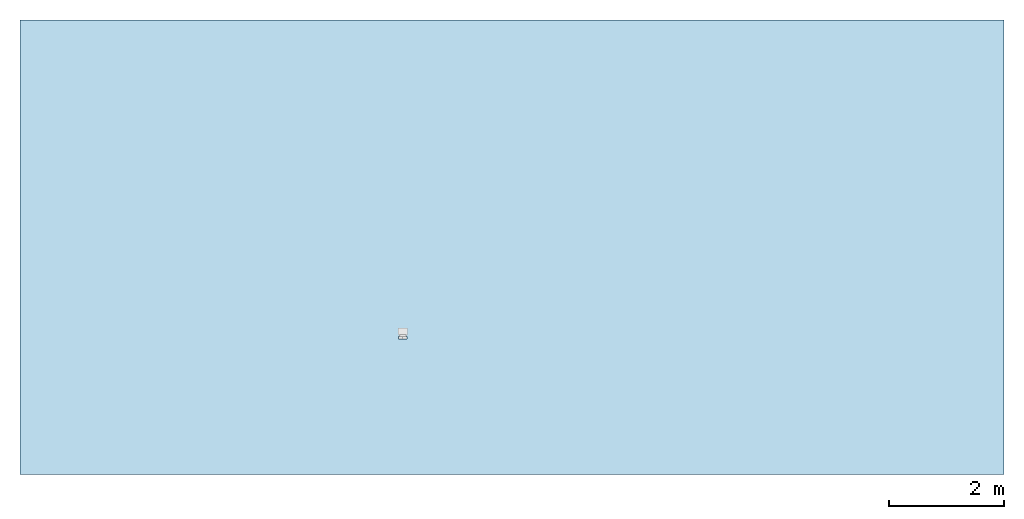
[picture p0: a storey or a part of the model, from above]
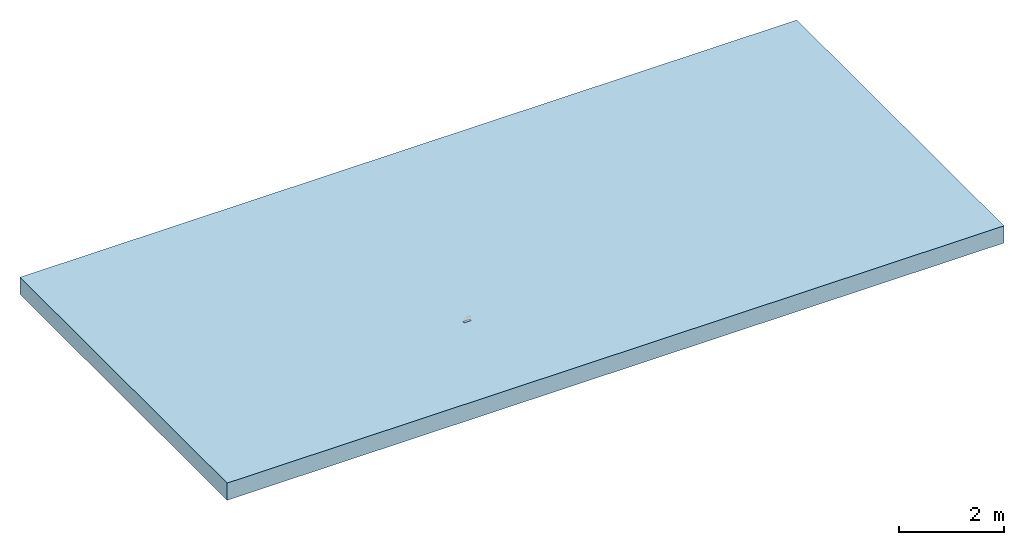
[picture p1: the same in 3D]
Properties of the parts of a building model (IFC2X3)

# File
Description: ViewDefinition [CoordinationView]
File name: 4962 - LH Inlet Outlet End cap.ifc
Time: 2013-08-30T17:54:13
Written by: Autodesk Revit 2013
Made in: 20120221_2030(x64)

# IfcProject, Project Number
LongName: Project Name; Phase: Project Status

# IfcSite, Default
RefLatitude: 42, 21, 30, 344238; RefLongitude: -71, -3, -35, -194702; RefElevation: 0 mm

# IfcBuilding
Pset_BuildingCommon - NumberOfStoreys: 1
Other - Project Address: ## Street City, State Zip; Project Number: Project Number; Project Name: Project Name; Project Status: Project Status; Project Issue Date: Issue Date; Client Name: Owner

# IfcBuildingStorey, Level 1
LongName: Level 1; Elevation: 0 mm
Constraints - Elevation Base: 0; Elevation: 0 mm
Graphics - Line Weight: 1; Line Pattern: Center; Symbol at End 2 Default: yes; Color: 0; Symbol at End 1 Default: no; Symbol: M_Level Head - Circle: M_Level Head - Circle
Dimensions - Computation Height: 0 mm
Identity Data - Building Story: yes; Structural: no; Name: Level 1

# IfcBuildingElementProxy: 4962 - LH Inlet/Outlet End cap, Civil-Drainage-Channel-ACO-KerbDrain-SP480:4962 - LH Inlet/Outlet End cap:4962 - LH Inlet/Outlet End cap:758980
In: Level 1
Material: Acetal Resin, Black, ACO Polymer Concrete
Construction - SP480-500: no; Inlet/Outlet-RH: no; EndCap: no; Inlet/Outlet-LH: yes
Constraints - Moves With Nearby Elements: no; Level: Level: Level 1
Phasing - Phase Created: New Construction
Dimensions - Volume: 2869491 mm3; Void_Ext_Start: -5.3 mm; Void_Ext_End: 155.2 mm; Endcap void width: 159.957 mm; Floor Opening Width: 150 mm; Void_Length: -50 mm; Endcap void depth: 359 mm
Pset_BuildingElementProxyCommon - Reference: 4962 - LH Inlet/Outlet End cap
General - TagNumber: 0.000000 0.000000; SerialNumber: 0.000000
Identity Data - Fax: +44 (0)1462 815895; Telephone: +44 (0)1462 816666; Product Page URL: http://www.aco.co.uk/product_detail.php?id=3; OmniClass Number: 23.70.50.24; Product Code: 4962; Installation guidelines: http://www.aco.co.uk/download.php?id=120; Maintenance guidelines: http://www.aco.co.uk/download.php?id=120; Address: ACO Business Park, Hitchin Road, Shefford, Bedfordshire, United Kingdom SG17 5TE; Product brochure: http://www.aco.co.uk/download.php?id=120; e-mail Sales: customersupport@aco.co.uk; Assembly Description: Rain Water Drainage; Price: POA - contact ACO; Cost: 0; Model: ACO KerbDrain SP480; e-mail Technical: technical@aco.co.uk; URL: www.aco.co.uk; Manufacturer: ACO Technologies plc - ACO Water Management Division; OmniClass Title: Rainwater Removal; Model Description: Combined kerb and drainage system; Assembly Code: D2040; Type Comments: ACO KerbDrain SP480 splayed LH outlet end cap
Data - Concrete Surround Volume - Load Class A 15 - D 400 - Concrete Pavement: N/A; Installation - Concrete Grade: N/A; Invert Depth: N/A; Hydraulic Performance: N/A; Connection Pipe O.D: Ø160mm; Drainage Slot Width: N/A; Product Dimensions: 197mm x 150mm x 480mm (LxWxH); Channel C.S.A: N/A; Drainage Slot Intake area: N/A; ACO Hydraulic Design Software: N/A; Product Standard: N/A; Product Weight: 5.8 Kg; Concrete Surround Volume - Load Class A 15 - D 400 - Grass or Asphalt Pavement: N/A; Load Class: N/A
Green Building Properties - End Cap Recyclable: Fully recyclable; Channel Recyclable: N/A; Channel Recycled Material Content: N/A; End Cap Recycled Material Content.: 20% minimum
Materials and Finishes - Channel Colour: N/A; Channel Material: N/A; Connection Pipe Material: Medium Density Polyethylene; Connection Pipe Material Colour: Black; End Cap Colour: Grey Black; End Cap Material: Vienite® Synthetic Resin Concrete Medium Density Polyethylene
Other - Revision: 1; CreatedBy: www.aco.co.uk

# IfcOpeningElement: Opening
In: Level 1
Structural - Enable Analytical Model: no; Structural: no
Constraints - Height Offset From Level: 0 mm; Related to Mass: no; Room Bounding: yes; Level: Level: Level 1
Dimensions - Thickness: 400 mm; Area: 135090000 mm2; Volume: 54029286181 mm3; Perimeter: 50000 mm
Phasing - Phase Created: New Construction
Construction - Function: 0; Default Thickness: 400 mm
Analytical Properties - Roughness: 1; Absorptance: 0.1
Graphics - Coarse Scale Fill Color: 0
Materials and Finishes - Structural Material: Plant

# IfcSlab: Floor:Generic Floor - 400mm, Floor:Generic Floor - 400mm:193825
In: Level 1
PredefinedType: FLOOR; Material: Plant 400 mm
Structural - Enable Analytical Model: no; Structural: no
Constraints - Height Offset From Level: 0 mm; Related to Mass: no; Room Bounding: yes; Level: Level: Level 1
Dimensions - Thickness: 400 mm; Area: 135090000 mm2; Volume: 54029286181 mm3; Perimeter: 50000 mm
Phasing - Phase Created: New Construction
Pset_SlabCommon - Reference: Generic Floor - 400mm; IsExternal: no; LoadBearing: yes
Construction - Function: 0; Default Thickness: 400 mm
Analytical Properties - Roughness: 1; Absorptance: 0.1
Graphics - Coarse Scale Fill Color: 0
Materials and Finishes - Structural Material: Plant
